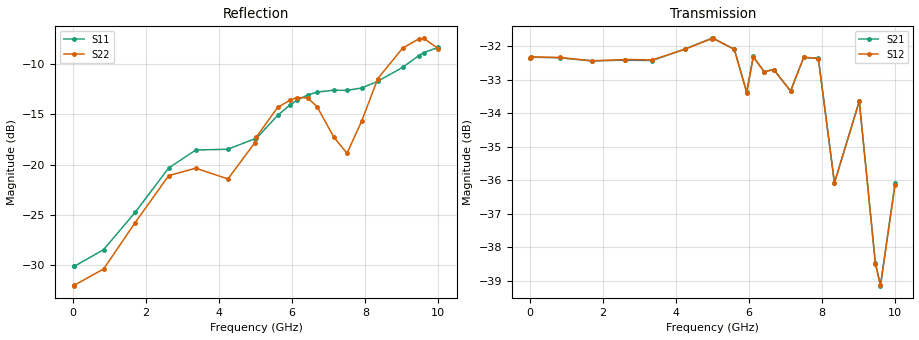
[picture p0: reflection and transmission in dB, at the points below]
! Integrated Device Technology
! Corporate Headquarters
! 6024 Silver Creek Valley Road
! San Jose, CA 95138  USA
! Phone:  1-408-284-8200
! Toll Free:  1-800-223-1366
! Webpage:  http://www.idt.com/
! Timing and RF Division
! 515 Groton Road, Suite 102
! Westford, MA 01886-6024
! Device:  F1958
! Description: 7-bit 0.25 dB Digital Step Attenuator
! Frequency:  0.001 -  6.000 GHz
! Package:  4x4 mm Thin QFN Plastic Package: 24 pin
! Ports:  2 RF, 12 DC
!  Pin  1  = D0
!  Pin  2  = VDD
!  Pin  3  = VMODE
!  Pin  4  = GND
!  Pin  5  = RF1  =  Port 1
!  Pin  6  = GND
!  Pin  7  = GND
!  Pin  8  = GND
!  Pin  9  = GND
!  Pin 10  = GND
!  Pin 11  = GND
!  Pin 12  = GND
!  Pin 13  = GND
!  Pin 14  = RF2  =  Port 2
!  Pin 15  = GND
!  Pin 16  = LE
!  Pin 17  = CLK
!  Pin 18  = DATA
!  Pin 19  = D6
!  Pin 20  = D5
!  Pin 21  = D4
!  Pin 22  = D3
!  Pin 23  = D2
!  Pin 24  = D1
! State:  126
! Atten State:  31.50 dB
! Voltage:  +3.30 Volts
! Current:  0.259 mA
! Data:  The device was measured on a F1958 evaluation board which has
!  individual transmission lines to the RF pins.  Data was collected
!  using a calibrated network analyzer.  The evaluation board was
!  de-embedded using Automatic Fixture Removal (AFR).
!  The reference plane is the edge of the package pin.
! Misc:
!  Action Tracker AT0419
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# GHz S dB R 50
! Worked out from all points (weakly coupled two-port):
!   500 points, 20 MHz to 10 GHz, reference 50 ohm
!   highest |S21| = -31.77 dB at 4.98 GHz (marker M1); lowest = -39.1 dB at 9.6 GHz (marker M2)
!   lowest |S11| = -30.1 dB at 40 MHz (marker M3), VSWR 1.06, Z = 47 - j0.0439 ohm
!   |S11| at or under -10 dB: start of sweep to 9.127 GHz
!   |S22| runs from -32.2 to -7.4 dB; largest |S21 - S12| = 0.00029
!   S11 on the Smith chart (normalised r, x): 20 MHz: 0.94, -0.00; 6.42 GHz: 0.67, +0.17; 10 GHz: 0.67, +0.59
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0.02  -30.06 -178.9  -32.35 -0.1  -32.35 -0.1  -32.02 -178.8
0.04  -30.09 -179.1  -32.33 -0.2  -32.32 -0.2  -31.97 -178.3
0.84  -28.44 171.3  -32.35 -8.5  -32.34 -8.5  -30.36 172.9
1.7  -24.75 171.3  -32.44 -16.8  -32.44 -16.8  -25.77 171.9
2.62  -20.34 177.1  -32.42 -25.9  -32.40 -25.9  -21.10 -179.2
3.36  -18.56 -175.7  -32.43 -33.8  -32.41 -34.0  -20.36 -169.3
4.24  -18.48 -179.1  -32.09 -42.6  -32.10 -42.6  -21.43 169.1
4.98  -17.43 161.8  -31.77 -51.5  -31.78 -51.4  -17.82 137.9
5.02  -17.40 160.8  -31.77 -52.3  -31.77 -52.3  -17.26 138.4
5.6  -15.12 150.8  -32.09 -60.7  -32.10 -60.7  -14.33 140.2
5.94  -14.09 148.4  -33.37 -63.7  -33.39 -63.7  -13.62 148.5
6.12  -13.64 148.7  -32.31 -64.1  -32.33 -64.2  -13.35 151.4
6.42  -13.10 147.7  -32.76 -69.0  -32.77 -69.0  -13.38 156.9
6.68  -12.81 146.8  -32.70 -71.2  -32.70 -71.2  -14.26 157.4
7.14  -12.62 142.9  -33.34 -75.6  -33.34 -75.6  -17.30 151.5
7.5  -12.64 138.4  -32.34 -79.3  -32.33 -79.1  -18.88 119.6
7.9  -12.40 129.1  -32.36 -96.3  -32.37 -96.4  -15.69 89.1
8.34  -11.74 119.1  -36.08 -100.3  -36.07 -100.5  -11.48 83.9
9.02  -10.36 108.0  -33.64 -100.9  -33.65 -101.2  -8.45 97.7
9.46  -9.20 102.7  -38.45 -105.0  -38.49 -105.4  -7.54 106.8
9.6  -8.89 101.2  -39.14 -93.0  -39.13 -92.9  -7.48 110.5
10  -8.37 100.0  -36.07 -73.3  -36.14 -73.0  -8.51 113.8
